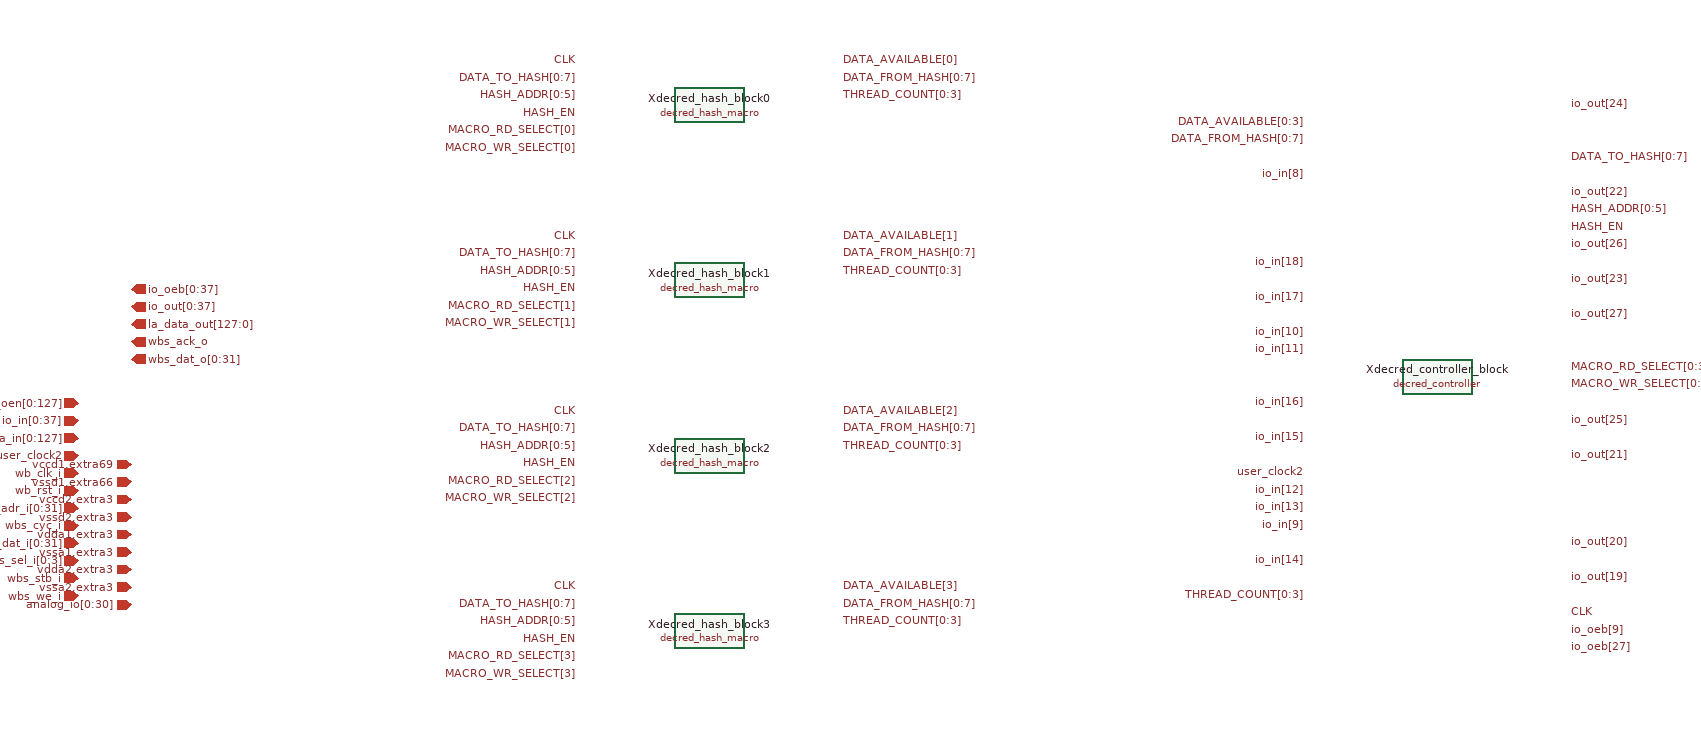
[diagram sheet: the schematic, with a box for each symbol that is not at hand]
v {xschem version=2.9.9 file_version=1.2 }
G {}
K {}
V {}
S {}
E {}
C {devices/lab_pin.sym} 750 -810 0 0 {name=p41 lab=CLK }
C {devices/lab_pin.sym} 1050 -810 0 1 {name=p42 lab=DATA_AVAILABLE[0] }
C {devices/lab_pin.sym} 1050 -790 0 1 {name=p43 lab=DATA_FROM_HASH[0:7] }
C {devices/lab_pin.sym} 750 -790 0 0 {name=p44 lab=DATA_TO_HASH[0:7] }
C {devices/lab_pin.sym} 750 -770 0 0 {name=p45 lab=HASH_ADDR[0:5] }
C {devices/lab_pin.sym} 750 -750 0 0 {name=p46 lab=HASH_EN }
C {devices/lab_pin.sym} 750 -730 0 0 {name=p47 lab=MACRO_RD_SELECT[0] }
C {devices/lab_pin.sym} 750 -710 0 0 {name=p48 lab=MACRO_WR_SELECT[0] }
C {devices/lab_pin.sym} 1050 -770 0 1 {name=p49 lab=THREAD_COUNT[0:3] }
C {decred_hash_macro/decred_hash_macro.sym} 900 -760 0 0 {name=Xdecred_hash_block0 }
C {devices/lab_pin.sym} 750 -610 0 0 {name=p50 lab=CLK }
C {devices/lab_pin.sym} 1050 -590 0 1 {name=p52 lab=DATA_FROM_HASH[0:7] }
C {devices/lab_pin.sym} 750 -590 0 0 {name=p53 lab=DATA_TO_HASH[0:7] }
C {devices/lab_pin.sym} 750 -570 0 0 {name=p54 lab=HASH_ADDR[0:5] }
C {devices/lab_pin.sym} 750 -550 0 0 {name=p55 lab=HASH_EN }
C {devices/lab_pin.sym} 750 -510 0 0 {name=p57 lab=MACRO_WR_SELECT[1] }
C {devices/lab_pin.sym} 1050 -570 0 1 {name=p58 lab=THREAD_COUNT[0:3] }
C {decred_hash_macro/decred_hash_macro.sym} 900 -560 0 0 {name=Xdecred_hash_block1 }
C {devices/lab_pin.sym} 750 -410 0 0 {name=p59 lab=CLK }
C {devices/lab_pin.sym} 1050 -390 0 1 {name=p61 lab=DATA_FROM_HASH[0:7] }
C {devices/lab_pin.sym} 750 -390 0 0 {name=p62 lab=DATA_TO_HASH[0:7] }
C {devices/lab_pin.sym} 750 -370 0 0 {name=p63 lab=HASH_ADDR[0:5] }
C {devices/lab_pin.sym} 750 -350 0 0 {name=p64 lab=HASH_EN }
C {devices/lab_pin.sym} 750 -310 0 0 {name=p66 lab=MACRO_WR_SELECT[2] }
C {devices/lab_pin.sym} 1050 -370 0 1 {name=p67 lab=THREAD_COUNT[0:3] }
C {decred_hash_macro/decred_hash_macro.sym} 900 -360 0 0 {name=Xdecred_hash_block2 }
C {devices/lab_pin.sym} 750 -210 0 0 {name=p68 lab=CLK }
C {devices/lab_pin.sym} 1050 -190 0 1 {name=p70 lab=DATA_FROM_HASH[0:7] }
C {devices/lab_pin.sym} 750 -190 0 0 {name=p71 lab=DATA_TO_HASH[0:7] }
C {devices/lab_pin.sym} 750 -170 0 0 {name=p72 lab=HASH_ADDR[0:5] }
C {devices/lab_pin.sym} 750 -150 0 0 {name=p73 lab=HASH_EN }
C {devices/lab_pin.sym} 750 -110 0 0 {name=p75 lab=MACRO_WR_SELECT[3] }
C {devices/lab_pin.sym} 1050 -170 0 1 {name=p76 lab=THREAD_COUNT[0:3] }
C {decred_hash_macro/decred_hash_macro.sym} 900 -160 0 0 {name=Xdecred_hash_block3 }
C {devices/lab_pin.sym} 1880 -760 0 1 {name=p77 lab=io_out[24] }
C {devices/lab_pin.sym} 1580 -740 0 0 {name=p78 lab=DATA_AVAILABLE[0:3] }
C {devices/lab_pin.sym} 1580 -720 0 0 {name=p79 lab=DATA_FROM_HASH[0:7] }
C {devices/lab_pin.sym} 1880 -700 0 1 {name=p80 lab=DATA_TO_HASH[0:7] }
C {devices/lab_pin.sym} 1580 -680 0 0 {name=p81 lab=io_in[8] }
C {devices/lab_pin.sym} 1880 -660 0 1 {name=p82 lab=io_out[22] }
C {devices/lab_pin.sym} 1880 -640 0 1 {name=p83 lab=HASH_ADDR[0:5] }
C {devices/lab_pin.sym} 1880 -620 0 1 {name=p84 lab=HASH_EN }
C {devices/lab_pin.sym} 1880 -600 0 1 {name=p85 lab=io_out[26] }
C {devices/lab_pin.sym} 1580 -580 0 0 {name=p86 lab=io_in[18] }
C {devices/lab_pin.sym} 1880 -560 0 1 {name=p87 lab=io_out[23] }
C {devices/lab_pin.sym} 1580 -540 0 0 {name=p88 lab=io_in[17] }
C {devices/lab_pin.sym} 1880 -520 0 1 {name=p89 lab=io_out[27] }
C {devices/lab_pin.sym} 1580 -500 0 0 {name=p90 lab=io_in[10] }
C {devices/lab_pin.sym} 1580 -480 0 0 {name=p91 lab=io_in[11] }
C {devices/lab_pin.sym} 1880 -460 0 1 {name=p92 lab=MACRO_RD_SELECT[0:3] }
C {devices/lab_pin.sym} 1880 -440 0 1 {name=p93 lab=MACRO_WR_SELECT[0:3] }
C {devices/lab_pin.sym} 1580 -420 0 0 {name=p94 lab=io_in[16] }
C {devices/lab_pin.sym} 1880 -400 0 1 {name=p95 lab=io_out[25] }
C {devices/lab_pin.sym} 1580 -380 0 0 {name=p96 lab=io_in[15] }
C {devices/lab_pin.sym} 1880 -360 0 1 {name=p97 lab=io_out[21] }
C {devices/lab_pin.sym} 1580 -340 0 0 {name=p98 lab=user_clock2 }
C {devices/lab_pin.sym} 1580 -320 0 0 {name=p99 lab=io_in[12] }
C {devices/lab_pin.sym} 1580 -300 0 0 {name=p100 lab=io_in[13] }
C {devices/lab_pin.sym} 1580 -280 0 0 {name=p101 lab=io_in[9] }
C {devices/lab_pin.sym} 1880 -260 0 1 {name=p102 lab=io_out[20] }
C {devices/lab_pin.sym} 1580 -240 0 0 {name=p103 lab=io_in[14] }
C {devices/lab_pin.sym} 1880 -220 0 1 {name=p104 lab=io_out[19] }
C {devices/lab_pin.sym} 1580 -200 0 0 {name=p105 lab=THREAD_COUNT[0:3] }
C {devices/lab_pin.sym} 1880 -180 0 1 {name=p106 lab=CLK }
C {devices/lab_pin.sym} 1880 -160 0 1 {name=p107 lab=io_oeb[9] }
C {devices/lab_pin.sym} 1880 -140 0 1 {name=p108 lab=io_oeb[27] }
C {decred_hash_macro/decred_controller.sym} 1730 -450 0 0 {name=Xdecred_controller_block }
C {devices/title.sym} 160 -30 0 0 {name=l1 author="Stefan Schippers"}
C {devices/lab_pin.sym} 1050 -610 0 1 {name=p1 lab=DATA_AVAILABLE[1] }
C {devices/lab_pin.sym} 1050 -410 0 1 {name=p2 lab=DATA_AVAILABLE[2] }
C {devices/lab_pin.sym} 1050 -210 0 1 {name=p3 lab=DATA_AVAILABLE[3] }
C {devices/lab_pin.sym} 750 -530 0 0 {name=p4 lab=MACRO_RD_SELECT[1] }
C {devices/lab_pin.sym} 750 -330 0 0 {name=p5 lab=MACRO_RD_SELECT[2] }
C {devices/lab_pin.sym} 750 -130 0 0 {name=p6 lab=MACRO_RD_SELECT[3] }
C {devices/iopin.sym} 240 -190 0 0 {name=p109 lab=analog_io[0:30]}
C {devices/ipin.sym} 180 -400 0 0 {name=p110 lab=io_in[0:37]}
C {devices/opin.sym} 240 -550 0 0 {name=p111 lab=io_oeb[0:37]}
C {devices/opin.sym} 240 -530 0 0 {name=p112 lab=io_out[0:37]}
C {devices/ipin.sym} 180 -380 0 0 {name=p113 lab=la_data_in[0:127]}
C {devices/opin.sym} 240 -510 0 0 {name=p114 lab=la_data_out[127:0] }
C {devices/ipin.sym} 180 -420 0 0 {name=p115 lab=la_oen[0:127] }
C {devices/ipin.sym} 180 -360 0 0 {name=p117 lab=user_clock2 }
C {devices/ipin.sym} 180 -340 0 0 {name=p118 lab=wb_clk_i }
C {devices/ipin.sym} 180 -320 0 0 {name=p119 lab=wb_rst_i }
C {devices/opin.sym} 240 -490 0 0 {name=p120 lab=wbs_ack_o }
C {devices/ipin.sym} 180 -300 0 0 {name=p121 lab=wbs_adr_i[0:31]}
C {devices/ipin.sym} 180 -280 0 0 {name=p122 lab=wbs_cyc_i }
C {devices/ipin.sym} 180 -260 0 0 {name=p123 lab=wbs_dat_i[0:31]}
C {devices/opin.sym} 240 -470 0 0 {name=p124 lab=wbs_dat_o[0:31]}
C {devices/ipin.sym} 180 -240 0 0 {name=p125 lab=wbs_sel_i[0:3] }
C {devices/ipin.sym} 180 -220 0 0 {name=p126 lab=wbs_stb_i }
C {devices/ipin.sym} 180 -200 0 0 {name=p127 lab=wbs_we_i }
C {devices/iopin.sym} 240 -350 0 0 {name=p129 lab=vccd1.extra69 }
C {devices/iopin.sym} 240 -330 0 0 {name=p130 lab=vssd1.extra66 }
C {devices/iopin.sym} 240 -310 0 0 {name=p131 lab=vccd2.extra3 }
C {devices/iopin.sym} 240 -290 0 0 {name=p132 lab=vssd2.extra3 }
C {devices/iopin.sym} 240 -270 0 0 {name=p133 lab=vdda1.extra3 }
C {devices/iopin.sym} 240 -250 0 0 {name=p134 lab=vssa1.extra3 }
C {devices/iopin.sym} 240 -230 0 0 {name=p135 lab=vdda2.extra3 }
C {devices/iopin.sym} 240 -210 0 0 {name=p136 lab=vssa2.extra3 }
